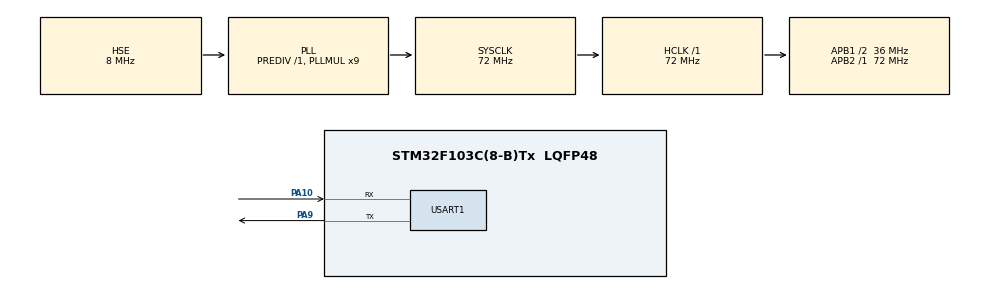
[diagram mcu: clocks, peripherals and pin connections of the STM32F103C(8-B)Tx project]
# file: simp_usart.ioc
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Mcu.Family=STM32F1
Mcu.Name=STM32F103C(8-B)Tx
Mcu.Package=LQFP48
NVIC.PriorityGroup=NVIC_PRIORITYGROUP_4
NVIC.USART1_IRQn=true\:0\:0\:false\:false\:true\:true
PA10.Mode=Asynchronous
PA10.Signal=USART1_RX
PA13.Mode=Serial_Wire
PA13.Signal=SYS_JTMS-SWDIO
PA14.Mode=Serial_Wire
PA14.Signal=SYS_JTCK-SWCLK
PA9.Mode=Asynchronous
PA9.Signal=USART1_TX
PD0-OSC_IN.Mode=HSE-External-Oscillator
PD0-OSC_IN.Signal=RCC_OSC_IN
PD1-OSC_OUT.Mode=HSE-External-Oscillator
PD1-OSC_OUT.Signal=RCC_OSC_OUT
ProjectManager.HeapSize=0x200
ProjectManager.StackSize=0x400
ProjectManager.TargetToolchain=TrueSTUDIO
RCC.AHBFreq_Value=72000000
RCC.APB1CLKDivider=RCC_HCLK_DIV2
RCC.APB1Freq_Value=36000000
RCC.APB1TimFreq_Value=72000000
RCC.APB2Freq_Value=72000000
RCC.APB2TimFreq_Value=72000000
RCC.HCLKFreq_Value=72000000
RCC.PLLMUL=RCC_PLL_MUL9
RCC.PLLSourceVirtual=RCC_PLLSOURCE_HSE
RCC.SYSCLKFreq_VALUE=72000000
RCC.SYSCLKSource=RCC_SYSCLKSOURCE_PLLCLK
RCC.USBFreq_Value=72000000
USART1.VirtualMode=VM_ASYNC
board=custom

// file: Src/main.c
/* USER CODE BEGIN Header */
/**
  ******************************************************************************
  * @file           : main.c
  * @brief          : Main program body
  ******************************************************************************
  ** This notice applies to any and all portions of this file
  * that are not between comment pairs USER CODE BEGIN and
  * USER CODE END. Other portions of this file, whether
  * inserted by the user or by software development tools
  * are owned by their respective copyright owners.
  *
  * COPYRIGHT(c) 2018 STMicroelectronics
  *
  * Redistribution and use in source and binary forms, with or without modification,
  * are permitted provided that the following conditions are met:
  *   1. Redistributions of source code must retain the above copyright notice,
  *      this list of conditions and the following disclaimer.
  *   2. Redistributions in binary form must reproduce the above copyright notice,
  *      this list of conditions and the following disclaimer in the documentation
  *      and/or other materials provided with the distribution.
  *   3. Neither the name of STMicroelectronics nor the names of its contributors
  *      may be used to endorse or promote products derived from this software
  *      without specific prior written permission.
  *
  * THIS SOFTWARE IS PROVIDED BY THE COPYRIGHT HOLDERS AND CONTRIBUTORS "AS IS"
  * AND ANY EXPRESS OR IMPLIED WARRANTIES, INCLUDING, BUT NOT LIMITED TO, THE
  * IMPLIED WARRANTIES OF MERCHANTABILITY AND FITNESS FOR A PARTICULAR PURPOSE ARE
  * DISCLAIMED. IN NO EVENT SHALL THE COPYRIGHT HOLDER OR CONTRIBUTORS BE LIABLE
  * FOR ANY DIRECT, INDIRECT, INCIDENTAL, SPECIAL, EXEMPLARY, OR CONSEQUENTIAL
  * DAMAGES (INCLUDING, BUT NOT LIMITED TO, PROCUREMENT OF SUBSTITUTE GOODS OR
  * SERVICES; LOSS OF USE, DATA, OR PROFITS; OR BUSINESS INTERRUPTION) HOWEVER
  * CAUSED AND ON ANY THEORY OF LIABILITY, WHETHER IN CONTRACT, STRICT LIABILITY,
  * OR TORT (INCLUDING NEGLIGENCE OR OTHERWISE) ARISING IN ANY WAY OUT OF THE USE
  * OF THIS SOFTWARE, EVEN IF ADVISED OF THE POSSIBILITY OF SUCH DAMAGE.
  *
  ******************************************************************************
  */
/* USER CODE END Header */

#include "main.h"

/* USER CODE BEGIN Includes */

#include "string.h" // для функции snprintf

/* USER CODE END Includes */

/* USER CODE BEGIN PD */

#define BUFSIZE 64  // размер массива для приёма (указать нужный)
#define TRANSIZE 96 // размер массива для отправки (указать нужный)

/* USER CODE END PD */

UART_HandleTypeDef huart1;

/* USER CODE BEGIN PV */

uint8_t rec;
uint8_t receiveBuffer[BUFSIZE] = {0,};
char uart1_str[TRANSIZE] = {0,};
volatile int i = -1;
volatile int count = 0;
volatile uint8_t rec_flag = 0;

/* USER CODE END PV */

void SystemClock_Config(void);
static void MX_GPIO_Init(void);
static void MX_USART1_UART_Init(void);

/* USER CODE BEGIN 0 */

void HAL_UART_RxCpltCallback(UART_HandleTypeDef *huart) // колбек, вызываемый прерыванием от приёму от уарта
{
	if(huart == &huart1) // если задействован только один УАРТ, то это условие можно убрать
	{
		i++;
		receiveBuffer[i] = rec; // складываем принятые байты в массив

		if(rec == '\n' || i > BUFSIZE - 3) // проверяем пришёл ли "символ новой строки" и подстраховываемся от переполнения массива
		{
			i++;
			receiveBuffer[i] = 0; // зануляем конец строки (массива)
			//snprintf(uart1_str, TRANSIZE - 1, "%d UART1 %d - %s\n", count++, i, receiveBuffer);
			//HAL_UART_Transmit(&huart1, (uint8_t*)uart1_str, strlen(uart1_str), 1000);
			rec_flag = 1;
			i = -1;
			HAL_GPIO_TogglePin(pa3_GPIO_Port, pa3_Pin);
		}

		if(!rec_flag) HAL_UART_Receive_IT(&huart1, &rec, 1); // инициируем прерывание по приёму байта
	}
}

/* USER CODE END 0 */

int main(void)
{
  /* USER CODE BEGIN 1 */

  char trans_str[TRANSIZE] = {0,};
  int i = 0;

  /* USER CODE END 1 */

  /* MCU Configuration--------------------------------------------------------*/

  /* Reset of all peripherals, Initializes the Flash interface and the Systick. */
  HAL_Init();

  /* Configure the system clock */
  SystemClock_Config();

  /* Initialize all configured peripherals */
  MX_GPIO_Init();
  MX_USART1_UART_Init();
  /* USER CODE BEGIN 2 */

  HAL_UART_Receive_IT(&huart1, &rec, 1); // инициируем прерывание по приёму байта

  /* USER CODE END 2 */

  /* Infinite loop */
  while (1)
  {

    /* USER CODE BEGIN 3 */

	  if(rec_flag == 1)
	  {
		  int l = strlen((char*)receiveBuffer);
		  snprintf(trans_str, TRANSIZE - 1, "Wait %d Reciv %d - %s\n", i++, l, receiveBuffer); // собираем строку для отправки
		  HAL_UART_Transmit(&huart1, (uint8_t*)trans_str, strlen(trans_str), 1000);
		  rec_flag = 0;
		  HAL_UART_Receive_IT(&huart1, &rec, 1);
	  }
  }
  /* USER CODE END 3 */
}

void SystemClock_Config(void)
{
  RCC_OscInitTypeDef RCC_OscInitStruct = {0};
  RCC_ClkInitTypeDef RCC_ClkInitStruct = {0};

  /**Initializes the CPU, AHB and APB busses clocks
  */
  RCC_OscInitStruct.OscillatorType = RCC_OSCILLATORTYPE_HSE;
  RCC_OscInitStruct.HSEState = RCC_HSE_ON;
  RCC_OscInitStruct.HSEPredivValue = RCC_HSE_PREDIV_DIV1;
  RCC_OscInitStruct.HSIState = RCC_HSI_ON;
  RCC_OscInitStruct.PLL.PLLState = RCC_PLL_ON;
  RCC_OscInitStruct.PLL.PLLSource = RCC_PLLSOURCE_HSE;
  RCC_OscInitStruct.PLL.PLLMUL = RCC_PLL_MUL9;
  if (HAL_RCC_OscConfig(&RCC_OscInitStruct) != HAL_OK)
  {
    Error_Handler();
  }
  /**Initializes the CPU, AHB and APB busses clocks
  */
  RCC_ClkInitStruct.ClockType = RCC_CLOCKTYPE_HCLK|RCC_CLOCKTYPE_SYSCLK
                              |RCC_CLOCKTYPE_PCLK1|RCC_CLOCKTYPE_PCLK2;
  RCC_ClkInitStruct.SYSCLKSource = RCC_SYSCLKSOURCE_PLLCLK;
  RCC_ClkInitStruct.AHBCLKDivider = RCC_SYSCLK_DIV1;
  RCC_ClkInitStruct.APB1CLKDivider = RCC_HCLK_DIV2;
  RCC_ClkInitStruct.APB2CLKDivider = RCC_HCLK_DIV1;

  if (HAL_RCC_ClockConfig(&RCC_ClkInitStruct, FLASH_LATENCY_2) != HAL_OK)
  {
    Error_Handler();
  }
}

static void MX_USART1_UART_Init(void)
{

  huart1.Instance = USART1;
  huart1.Init.BaudRate = 115200;
  huart1.Init.WordLength = UART_WORDLENGTH_8B;
  huart1.Init.StopBits = UART_STOPBITS_1;
  huart1.Init.Parity = UART_PARITY_NONE;
  huart1.Init.Mode = UART_MODE_TX_RX;
  huart1.Init.HwFlowCtl = UART_HWCONTROL_NONE;
  huart1.Init.OverSampling = UART_OVERSAMPLING_16;
  if (HAL_UART_Init(&huart1) != HAL_OK)
  {
    Error_Handler();
  }

}

static void MX_GPIO_Init(void)
{
  GPIO_InitTypeDef GPIO_InitStruct = {0};

  /* GPIO Ports Clock Enable */
  __HAL_RCC_GPIOC_CLK_ENABLE();
  __HAL_RCC_GPIOD_CLK_ENABLE();
  __HAL_RCC_GPIOA_CLK_ENABLE();

  /*Configure GPIO pin Output Level */
  HAL_GPIO_WritePin(led13_GPIO_Port, led13_Pin, GPIO_PIN_SET);

  /*Configure GPIO pin Output Level */
  HAL_GPIO_WritePin(pa3_GPIO_Port, pa3_Pin, GPIO_PIN_RESET);

  /*Configure GPIO pin : led13_Pin */
  GPIO_InitStruct.Pin = led13_Pin;
  GPIO_InitStruct.Mode = GPIO_MODE_OUTPUT_PP;
  GPIO_InitStruct.Pull = GPIO_NOPULL;
  GPIO_InitStruct.Speed = GPIO_SPEED_FREQ_LOW;
  HAL_GPIO_Init(led13_GPIO_Port, &GPIO_InitStruct);

  /*Configure GPIO pin : pa3_Pin */
  GPIO_InitStruct.Pin = pa3_Pin;
  GPIO_InitStruct.Mode = GPIO_MODE_OUTPUT_PP;
  GPIO_InitStruct.Pull = GPIO_NOPULL;
  GPIO_InitStruct.Speed = GPIO_SPEED_FREQ_LOW;
  HAL_GPIO_Init(pa3_GPIO_Port, &GPIO_InitStruct);

}

void Error_Handler(void)
{
  /* USER CODE BEGIN Error_Handler_Debug */
  /* User can add his own implementation to report the HAL error return state */
	//printf("Wrong parameters value: file on line\r\n");
  /* USER CODE END Error_Handler_Debug */
}

#ifdef  USE_FULL_ASSERT
/**
  * @brief  Reports the name of the source file and the source line number
  *         where the assert_param error has occurred.
  * @param  file: pointer to the source file name
  * @param  line: assert_param error line source number
  * @retval None
  */
void assert_failed(uint8_t *file, uint32_t line)
{
  /* USER CODE BEGIN 6 */
  /* User can add his own implementation to report the file name and line number,
     tex: printf("Wrong parameters value: file %s on line %d\r\n", file, line) */
	//printf("Werererene\r\n");
  /* USER CODE END 6 */
}
#endif /* USE_FULL_ASSERT */

/************************ (C) COPYRIGHT STMicroelectronics *****END OF FILE****/
